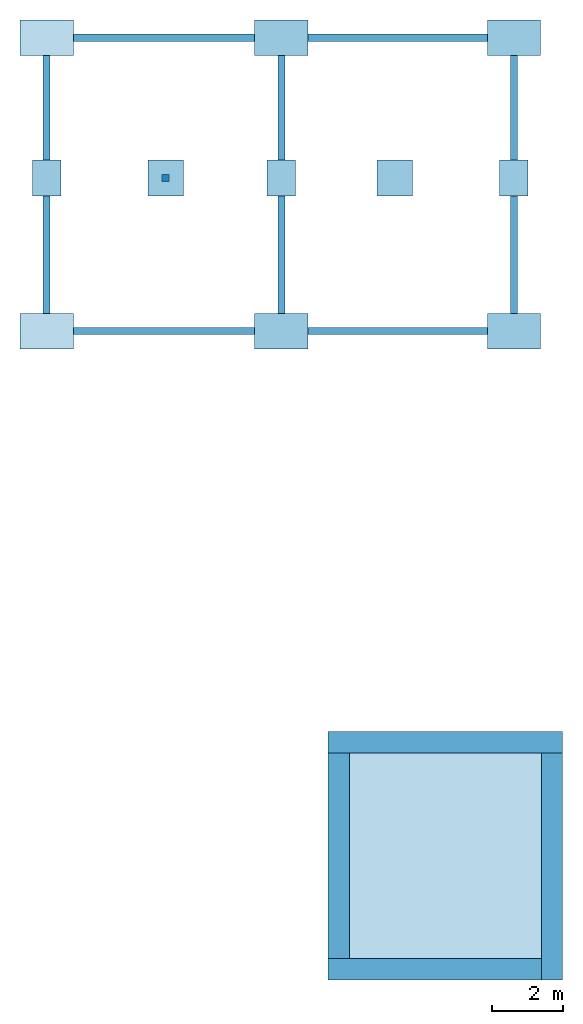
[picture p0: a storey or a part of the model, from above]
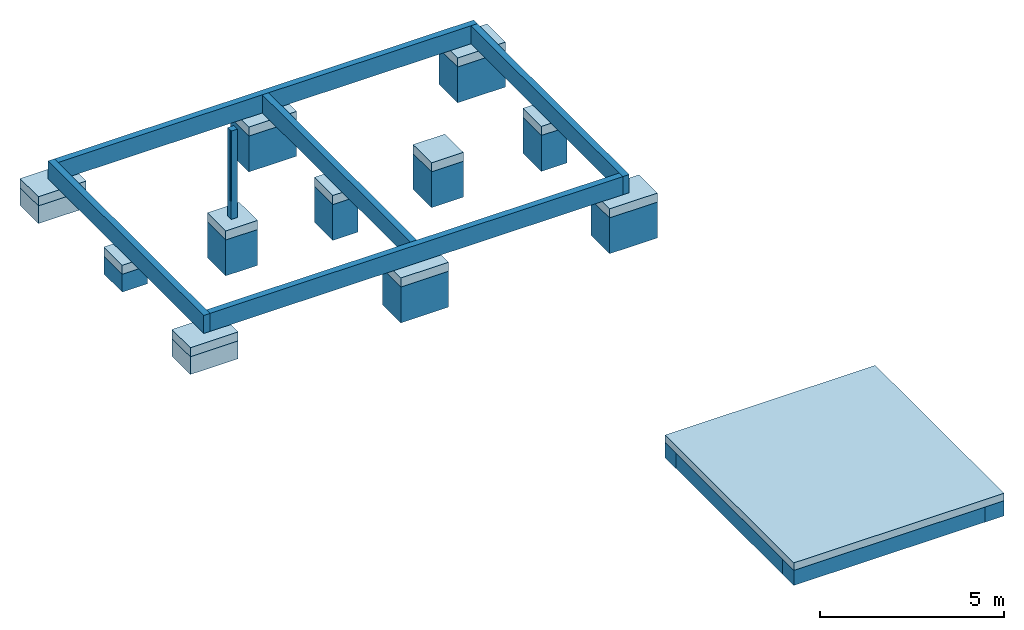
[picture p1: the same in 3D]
Properties of the parts of a building model (IFC2X3)

# File
Description: ViewDefinition [CoordinationView, QuantityTakeOffAddOnView, FMHandOverView]
Time: 2016-03-23T11:02:19
Written by: The EXPRESS Data Manager Version 5.02.0100.07 : 28 Aug 2013
Made in: 20150714_1515(x64) - Exporter 16.3.0.0 - Interface alternative d'export 16.3.0.0
Comment: STEP Physical File produced by: The EXPRESS Data Manager Version 5.02.0100.07 : 28 Aug 2013 * Module: EDMstepFileFactory/EDMstandAlone * Creation date: Wed Mar 23 11:02:19 2016 * Host: St�phaneBertran * Database: C:\Users\STPHAN~1\AppData\Local\Temp\{4BC35CA4-EAC2-46B8-98C0-8E4794780E52}\ifc * Database version: 5507 * Database creation date: Wed Mar 23 11:02:09 2016 * Schema: IFC2X3 * Model: DataRepository.ifc * Model creation date: Wed Mar 23 11:02:10 2016 * Header model: DataRepository.ifc_HeaderModel * Header model creation date: Wed Mar 23 11:02:10 2016 * EDMuser: sdai-user * EDMgroup: sdai-group * License ID and type: 5605 : Permanent license. Expiry date: * EDMstepFileFactory options: 020000

# IfcProject
LongName: E:\02 Année scolaire 2015 2016\01 Seconde TEBEE\07 Projet Damparis\Travail demandé\Nouveau dossier\pavillon et garage.ifc

# IfcSite, Surface:187648
RefLatitude: 48, 51, 23, 999632; RefLongitude: 2, 21, 3, 553904; RefElevation: 0 m

# IfcBuilding
Pset_BuildingCommon - NumberOfStoreys: 4

# IfcBuildingStorey (4)
Name | LongName | Elevation (m)
soubassement | soubassement | -0.6
Rez de chaussée | Rez de chaussée | 0
Plan étage | Plan étage | 2.74
Plan de couverture | Plan de couverture | 5.3

# IfcSpace (2)
In: Rez de chaussée
InteriorOrExteriorSpace: INTERNAL
BaseQuantities - NetFloorArea: 19.5488 m2; Height: 2.4384 m; GrossPerimeter: 19.08 m; GrossFloorArea: 19.5488 m2
Name | LongName | Reference
1 | Garage 1 | Garage 1 1
2 | Garage 2 | Garage 2 2

# IfcBeam: Poutre rectangulaire - Béton:200 x 400 mm:273551 (2)
In: Rez de chaussée
Material: Maçonnerie - Béton
Pset_BeamCommon - IsExternal: no; LoadBearing: yes; Slope: 0 deg; Reference: 200 x 400 mm; Span: 6.53 m
Name (Poutre rectangulaire - Béton:200 x 400 mm:...) | GrossVolume (m3)
274924 | 0.21164
275096 | 0.211528

# IfcColumn: 200 x 200 mm (2)
Type - ElementType: 200 x 200 mm; PredefinedType: COLUMN; Material: Maçonnerie - Béton
Pset_ColumnCommon - LoadBearing: no; IsExternal: no; Reference: 200 x 200 mm
Name (Poteau rectangulaire:200 x 200 mm:...) | In | GrossVolume (m3)
187471 | soubassement | 0.115845
187492 | Rez de chaussée | 0.1176 | BaseQuantities - Length: 2.94 m; CrossSectionArea: 0.04 m2; OuterSurfaceArea: 2.432 m2; Pset_ColumnCommon - Slope: 0 deg

# IfcCovering: Plafond composé:Plafond avec isolation, Plafond composé:Plafond avec isolation:277230
In: Plan étage
PredefinedType: CEILING; Material: Maçonnerie - Isolant 0.25 m, Faux-plafond - Trame 600 x 600 0.01 m
Pset_CoveringCommon - Reference: Plafond avec isolation; TotalThickness: 0.26 m
BaseQuantities - GrossCeilingArea: 104.458 m2

# IfcDoor: 93 x 210 - (90), FR_PVC Panneau Plein:93 x 210 - (90):286378
In: Rez de chaussée
Type - OperationType: SINGLE_SWING_LEFT; ParameterTakesPrecedence: no; Sizeable: no; Material: Poignée PVC, PVC Blanc
Type - FR_PVC Panneau Plein:93 x 210 - (90):286378 - PanelOperation: SWINGING
OverallHeight: 2.15 m; OverallWidth: 1.03 m
Pset_DoorCommon - IsExternal: no; Reference: 93 x 210 - (90)
BaseQuantities - Height: 2.1 m; Width: 0.93 m; Area: 1.953 m2

# IfcDoor: 93 x 210 - (90), FR_PVC Panneau Plein:93 x 210 - (90):286377
In: Rez de chaussée
Type - OperationType: SINGLE_SWING_RIGHT; ParameterTakesPrecedence: no; Sizeable: no; Material: Poignée PVC, PVC Blanc
Type - FR_PVC Panneau Plein:93 x 210 - (90):286377 - PanelOperation: SWINGING
OverallHeight: 2.15 m; OverallWidth: 1.03 m
Pset_DoorCommon - IsExternal: no; Reference: 93 x 210 - (90)
BaseQuantities - Height: 2.1 m; Width: 0.93 m; Area: 1.953 m2

# IfcDoor: 96" x 78" (2)
In: Rez de chaussée
Type - ParameterTakesPrecedence: no; Sizeable: no; Classification: B2030410 Overhead Doors (Uniformat); Material: Rubber - Black
OverallHeight: 1.9812 m; OverallWidth: 2.4384 m
Pset_DoorCommon - IsExternal: no; Reference: 96" x 78"
BaseQuantities - Height: 1.9812 m; Width: 2.4384 m; Area: 4.83096 m2
Name (Overhead-Sectional-Flush:96" x 78":...)
286375
286376

# IfcDoor: PF 1.30 x 2.15 (3)
In: Rez de chaussée
Type - OperationType: DOUBLE_DOOR_SINGLE_SWING; ParameterTakesPrecedence: no; Sizeable: no; Classification: C1020 Interior Doors (Uniformat); Material: Glass, PVC - Blanc
Type - Double-Glass 1_no trim:PF 1.30 x 2.15:205899 - PanelOperation: SWINGING
OverallHeight: 2.15 m; OverallWidth: 1.3 m
Pset_DoorCommon - IsExternal: no; Reference: PF 1.30 x 2.15
BaseQuantities - Height: 2.15 m; Width: 1.3 m; Area: 2.795 m2
Name (Double-Glass 1_no trim:PF 1.30 x 2.15:...)
205899
205926
205958

# IfcDoor: PF 1.30 x 2.15, Double-Glass 1_no trim:PF 1.30 x 2.15:206001
In: Rez de chaussée
Type - OperationType: DOUBLE_DOOR_SINGLE_SWING; ParameterTakesPrecedence: no; Sizeable: no; Classification: C1020 Interior Doors (Uniformat); Material: Glass, PVC - Blanc
Type - Double-Glass 1_no trim:PF 1.30 x 2.15:206001 - PanelOperation: SWINGING
OverallHeight: 2.15 m; OverallWidth: 1.3 m
Pset_DoorCommon - IsExternal: no; Reference: PF 1.30 x 2.15
BaseQuantities - Height: 2.15 m; Width: 1.3 m; Area: 2.795 m2

# IfcDoor: PF 1.60 x 2.15 (2)
In: Rez de chaussée
Type - OperationType: DOUBLE_DOOR_SINGLE_SWING; ParameterTakesPrecedence: no; Sizeable: no; Classification: C1020 Interior Doors (Uniformat); Material: Glass, PVC - Blanc
Type - Double-Glass 1_no trim:PF 1.60 x 2.15:205161 - PanelOperation: SWINGING
OverallHeight: 2.15 m; OverallWidth: 1.6 m
Pset_DoorCommon - IsExternal: no; Reference: PF 1.60 x 2.15
BaseQuantities - Height: 2.15 m; Width: 1.6 m; Area: 3.44 m2
Name (Double-Glass 1_no trim:PF 1.60 x 2.15:...)
205161
205435

# IfcDoor: PP (0.83m x 2.04m) (5)
Type - OperationType: SINGLE_SWING_LEFT; ParameterTakesPrecedence: no; Sizeable: no; Material: Finition Peinture - Blanc satiné, Bois - Panneau de porte, Bois - Cadre de porte
Type - Int. Simple:PP (0.83m x 2.04m):187630 - PanelOperation: SWINGING
OverallHeight: 2.075 m; OverallWidth: 0.9 m
Pset_DoorCommon - IsExternal: no; Reference: PP (0.83m x 2.04m)
BaseQuantities - Height: 2.04 m; Width: 0.83 m; Area: 1.6932 m2
Name (Int. Simple:PP (0.83m x 2.04m):...) | In
187630 | Plan étage
187632 | Plan étage
187636 | Plan étage
187641 | Plan étage
206475 | Rez de chaussée

# IfcDoor: PP (0.83m x 2.04m), Int. Simple:PP (0.83m x 2.04m):187644
In: Plan étage
Type - OperationType: SINGLE_SWING_LEFT; ParameterTakesPrecedence: no; Sizeable: no; Material: Finition Peinture - Blanc satiné, Bois - Panneau de porte, Bois - Cadre de porte
Type - Int. Simple:PP (0.83m x 2.04m):187644 - PanelOperation: SWINGING
OverallHeight: 2.075 m; OverallWidth: 0.9 m
Pset_DoorCommon - IsExternal: no; Reference: PP (0.83m x 2.04m)
BaseQuantities - Height: 2.04 m; Width: 0.83 m; Area: 1.6932 m2

# IfcDoor: PP (0.83m x 2.04m), Int. Simple:PP (0.83m x 2.04m):206517
In: Rez de chaussée
Type - OperationType: SINGLE_SWING_LEFT; ParameterTakesPrecedence: no; Sizeable: no; Material: Finition Peinture - Blanc satiné, Bois - Panneau de porte, Bois - Cadre de porte
Type - Int. Simple:PP (0.83m x 2.04m):206517 - PanelOperation: SWINGING
OverallHeight: 2.075 m; OverallWidth: 0.9 m
Pset_DoorCommon - IsExternal: no; Reference: PP (0.83m x 2.04m)
BaseQuantities - Height: 2.04 m; Width: 0.83 m; Area: 1.6932 m2

# IfcDoor: PP (0.83m x 2.04m), Int. Simple:PP (0.83m x 2.04m):206587
In: Rez de chaussée
Type - OperationType: SINGLE_SWING_LEFT; ParameterTakesPrecedence: no; Sizeable: no; Material: Finition Peinture - Blanc satiné, Bois - Panneau de porte, Bois - Cadre de porte
Type - Int. Simple:PP (0.83m x 2.04m):206587 - PanelOperation: SWINGING
OverallHeight: 2.075 m; OverallWidth: 0.9 m
Pset_DoorCommon - IsExternal: no; Reference: PP (0.83m x 2.04m)
BaseQuantities - Height: 2.04 m; Width: 0.83 m; Area: 1.6932 m2

# IfcDoor: PP (0.83m x 2.04m) (6)
Type - OperationType: SINGLE_SWING_RIGHT; ParameterTakesPrecedence: no; Sizeable: no; Material: Finition Peinture - Blanc satiné, Bois - Panneau de porte, Bois - Cadre de porte
Type - Int. Simple:PP (0.83m x 2.04m):187629 - PanelOperation: SWINGING
OverallHeight: 2.075 m; OverallWidth: 0.9 m
Pset_DoorCommon - IsExternal: no; Reference: PP (0.83m x 2.04m)
BaseQuantities - Height: 2.04 m; Width: 0.83 m; Area: 1.6932 m2
Name (Int. Simple:PP (0.83m x 2.04m):...) | In
187629 | Plan étage
187631 | Plan étage
187635 | Plan étage
187647 | Plan étage
206419 | Rez de chaussée
206630 | Rez de chaussée

# IfcDoor: PP (0.83m x 2.04m) (2)
Type - OperationType: SINGLE_SWING_RIGHT; ParameterTakesPrecedence: no; Sizeable: no; Material: Finition Peinture - Blanc satiné, Bois - Panneau de porte, Bois - Cadre de porte
Type - Int. Simple:PP (0.83m x 2.04m):187633 - PanelOperation: SWINGING
OverallHeight: 2.075 m; OverallWidth: 0.9 m
Pset_DoorCommon - IsExternal: no; Reference: PP (0.83m x 2.04m)
BaseQuantities - Height: 2.04 m; Width: 0.83 m; Area: 1.6932 m2
Name (Int. Simple:PP (0.83m x 2.04m):...) | In
187633 | Plan étage
206556 | Rez de chaussée

# IfcDoor: PP Lisse (0.90m x 2.15m), Porte d'entrée:PP Lisse (0.90m x 2.15m):187528
In: Rez de chaussée
Type - OperationType: SINGLE_SWING_LEFT; ParameterTakesPrecedence: no; Sizeable: no; Material: Porte d'entrée - Poignée, Porte d'entrée - Panneau, Porte d'entrée - Cadre
Type - Porte d'entrée:PP Lisse (0.90m x 2.15m):187528 - PanelOperation: SWINGING
OverallHeight: 2.19 m; OverallWidth: 0.98 m
Pset_DoorCommon - IsExternal: no; Reference: PP Lisse (0.90m x 2.15m)
BaseQuantities - Height: 2.15 m; Width: 0.9 m; Area: 1.935 m2

# IfcDoor: PP Lisse (0.90m x 2.15m), Porte d'entrée:PP Lisse (0.90m x 2.15m):205515
In: Rez de chaussée
Type - OperationType: SINGLE_SWING_RIGHT; ParameterTakesPrecedence: no; Sizeable: no; Material: Porte d'entrée - Poignée, Porte d'entrée - Panneau, Porte d'entrée - Cadre
Type - Porte d'entrée:PP Lisse (0.90m x 2.15m):205515 - PanelOperation: SWINGING
OverallHeight: 2.19 m; OverallWidth: 0.98 m
Pset_DoorCommon - IsExternal: no; Reference: PP Lisse (0.90m x 2.15m)
BaseQuantities - Height: 2.15 m; Width: 0.9 m; Area: 1.935 m2

# IfcDoor: Placard coulissante - 3 panneaux (2)
In: Rez de chaussée
Type - OperationType: SLIDING_TO_RIGHT; ParameterTakesPrecedence: no; Sizeable: no; Material: Placard - Profil, Placard - Encadrement, Placard - Porte
Type - Placard coulissante - 3 panneaux:Placard coulissante - 3 panneaux:187537 - PanelOperation: SLIDING
OverallHeight: 2.1 m; OverallWidth: 1.7 m
Pset_DoorCommon - IsExternal: no; Reference: Placard coulissante - 3 panneaux
BaseQuantities - Height: 2.1 m; Width: 1.7 m; Area: 3.57 m2
Name (Placard coulissante - 3 panneaux:Placard coulissante - 3 panneaux:...)
187537
204080

# IfcOpeningElement: Opening (46)
Name | In | Depth (m) | Height (m) | Width (m)
Mur de base:Int. plâtre 50 mm:187323 | Rez de chaussée | 6.2591 | 6.2591 | 3.12955
Mur de base:Int. plâtre 50 mm:187323 | Rez de chaussée | 0.05 | BaseQuantities - Area: 0.465543 m2
Mur de base:Int. plâtre 50 mm:187338 | Rez de chaussée | 6.2591 | 6.2591 | 3.12955
Overhead-Sectional-Flush:96" x 78":286376:1 | Rez de chaussée | 0.22 | 2.4384 | 1.9812
Mur de base:Int. plâtre 50 mm:187338 | Rez de chaussée | 0.05 | BaseQuantities - Area: 0.465543 m2
Mur de base:Int. plâtre 50 mm:187425 | Rez de chaussée | 0.05 | 0.025 | 2.1
Mur de base:Int. plâtre 50 mm:187440 | Rez de chaussée | 0.05 | 0.025 | 2.1
Mur de base:Int. plâtre 50 mm:187620 | Plan étage | 0.9 | 2.075 | 0.05
Mur de base:Int. plâtre 50 mm:187634 | Plan étage | 0.9 | 2.075 | 0.05
Overhead-Sectional-Flush:96" x 78":286375:1 | Rez de chaussée | 0.22 | 2.4384 | 1.9812
Double-Glass 1_no trim:PF 1.30 x 2.15:205899:1 | Rez de chaussée | 0.34 | 1.3 | 2.15
Double-Glass 1_no trim:PF 1.30 x 2.15:205926:1 | Rez de chaussée | 0.34 | 1.3 | 2.15
Double-Glass 1_no trim:PF 1.30 x 2.15:205958:1 | Rez de chaussée | 0.34 | 1.3 | 2.15
Double-Glass 1_no trim:PF 1.30 x 2.15:206001:1 | Rez de chaussée | 0.34 | 1.3 | 2.15
2 x Mur de base:Mur de base Ext. Parpaing 20 + Isolant 12:187495 | Rez de chaussée
Double-Glass 1_no trim:PF 1.60 x 2.15:205161:1 | Rez de chaussée | 0.34 | 1.6 | 2.15
Double-Glass 1_no trim:PF 1.60 x 2.15:205435:1 | Rez de chaussée | 0.34 | 1.6 | 2.15
Int. Simple:PP (0.83m x 2.04m):206419:1 | Rez de chaussée | 0.05 | 0.9 | 2.075
Int. Simple:PP (0.83m x 2.04m):206517:1 | Rez de chaussée | 0.05 | 0.9 | 2.075
Int. Simple:PP (0.83m x 2.04m):206587:1 | Rez de chaussée | 0.05 | 0.9 | 2.075
Placard coulissante - 3 panneaux:Placard coulissante - 3 panneaux:204080:1 | Rez de chaussée | 0.05 | 1.7 | 2.1
Int. Simple:PP (0.83m x 2.04m):206475:1 | Rez de chaussée | 0.05 | 0.9 | 2.075
Int. Simple:PP (0.83m x 2.04m):206556:1 | Rez de chaussée | 0.05 | 0.9 | 2.075
Int. Simple:PP (0.83m x 2.04m):206630:1 | Rez de chaussée | 0.05 | 0.9 | 2.075
Placard coulissante - 3 panneaux:Placard coulissante - 3 panneaux:187537:1 | Rez de chaussée | 0.05 | 1.7 | 2.1
Int. Simple:PP (0.83m x 2.04m):187630:1 | Plan étage | 0.05 | 0.9 | 2.075
Int. Simple:PP (0.83m x 2.04m):187631:1 | Plan étage | 0.05 | 0.9 | 2.075
Int. Simple:PP (0.83m x 2.04m):187629:1 | Plan étage | 0.05 | 0.9 | 2.075
Int. Simple:PP (0.83m x 2.04m):187633:1 | Plan étage | 0.05 | 0.9 | 2.075
Int. Simple:PP (0.83m x 2.04m):187632:1 | Plan étage | 0.05 | 0.9 | 2.075
Int. Simple:PP (0.83m x 2.04m):187635:1 | Plan étage | 0.05 | 0.9 | 2.075
Int. Simple:PP (0.83m x 2.04m):187636:1 | Plan étage | 0.05 | 0.9 | 2.075
Int. Simple:PP (0.83m x 2.04m):187641:1 | Plan étage | 0.05 | 0.9 | 2.075
Int. Simple:PP (0.83m x 2.04m):187644:1 | Plan étage | 0.05 | 0.9 | 2.075
Int. Simple:PP (0.83m x 2.04m):187647:1 | Plan étage | 0.05 | 0.9 | 2.075
4 x Mur de base:Mur de base Ext. Parpaing 20 + Isolant 12:188922 | Plan étage
4 x Mur de base:Mur de base Ext. Parpaing 20 + Isolant 12:188923 | Plan étage
2 x Mur de base:Ext.BBM + enduit 22:286370 | Rez de chaussée

# IfcRailing: Garde-corps:Type Bateau (3)
In: Rez de chaussée
Material: Peinture - grise, Bois - Pin
Pset_RailingCommon - IsExternal: no; Reference: Type Bateau; Height: 1.2192 m
Name (Garde-corps:Type Bateau:...) | Length (m)
223490 | 4.90433
227138 | 4.38474
271948 | 4.38474

# IfcRoof: Toit de base:Toit - 100 mm 2, Toit de base:Toit - 100 mm 2:286381
In: Plan étage
Pset_RoofCommon - IsExternal: yes; Reference: Toit - 100 mm 2; TotalArea: 61.8782 m2; ProjectedArea: 53.04 m2

# IfcRoof: Toit de base:Toit - 200 mm, Toit de base:Toit - 200 mm:277896
In: Plan de couverture
Pset_RoofCommon - IsExternal: yes; Reference: Toit - 200 mm; TotalArea: 143.325 m2; ProjectedArea: 122.854 m2

# IfcSlab: Base rectangulaire:1000mm x 1000mm x 300mm (2)
In: soubassement
PredefinedType: FLOOR; Material: Béton - Béton coulé sur place
Pset_SlabCommon - IsExternal: no; LoadBearing: yes; PitchAngle: 0 deg; Reference: 1000mm x 1000mm x 300mm
BaseQuantities - GrossArea: 1 m2; GrossVolume: 0.3 m3; Perimeter: 4 m; Width: 0.3 m
Name (Base rectangulaire:1000mm x 1000mm x 300mm:...)
215258
215662

# IfcSlab: Base rectangulaire:1500mm x 1000mm x 300mm (6)
In: soubassement
PredefinedType: FLOOR; Material: Béton - Béton coulé sur place
Pset_SlabCommon - IsExternal: no; LoadBearing: yes; Reference: 1500mm x 1000mm x 300mm; PitchAngle: 0 deg
BaseQuantities - GrossArea: 1.5 m2; GrossVolume: 0.45 m3; Perimeter: 5 m; Width: 0.3 m
Name (Base rectangulaire:1500mm x 1000mm x 300mm:...)
213384
213606
213688
213876
214012
214106

# IfcSlab: Base rectangulaire:800mm x 1000mm x 300mm (3)
In: soubassement
PredefinedType: FLOOR; Material: Béton - Béton coulé sur place
Pset_SlabCommon - IsExternal: no; LoadBearing: yes; PitchAngle: 0 deg; Reference: 800mm x 1000mm x 300mm
BaseQuantities - GrossArea: 0.8 m2; GrossVolume: 0.24 m3; Perimeter: 3.6 m; Width: 0.3 m
Name (Base rectangulaire:800mm x 1000mm x 300mm:...)
214496
214606
214724

# IfcSlab: Base rectangulaire:gros beton 1000mm x 1000mm x 1190mm (2)
In: soubassement
PredefinedType: FLOOR; Material: Béton - Béton coulé sur place
Pset_SlabCommon - IsExternal: no; LoadBearing: yes; PitchAngle: 0 deg; Reference: gros beton 1000mm x 1000mm x 1190mm
BaseQuantities - GrossArea: 1 m2; GrossVolume: 1.19 m3; Perimeter: 4 m; Width: 1.19 m
Name (Base rectangulaire:gros beton 1000mm x 1000mm x 1190mm:...)
216552
216665

# IfcSlab: Base rectangulaire:gros beton 1000mm x 800mm x 1190mm (2)
In: soubassement
PredefinedType: FLOOR; Material: Béton - Béton coulé sur place
Pset_SlabCommon - IsExternal: no; LoadBearing: yes; PitchAngle: 0 deg; Reference: gros beton 1000mm x 800mm x 1190mm
BaseQuantities - GrossArea: 0.8 m2; GrossVolume: 0.952 m3; Perimeter: 3.6 m; Width: 1.19 m
Name (Base rectangulaire:gros beton 1000mm x 800mm x 1190mm:...)
218791
218905

# IfcSlab: Base rectangulaire:gros beton 1000mm x 800mm x 590mm, Base rectangulaire:gros beton 1000mm x 800mm x 590mm:218621
In: soubassement
PredefinedType: FLOOR; Material: Béton - Béton coulé sur place
Pset_SlabCommon - IsExternal: no; LoadBearing: yes; PitchAngle: 0 deg; Reference: gros beton 1000mm x 800mm x 590mm
BaseQuantities - GrossArea: 0.8 m2; GrossVolume: 0.472 m3; Perimeter: 3.6 m; Width: 0.59 m

# IfcSlab: Base rectangulaire:gros beton 1500mm x 1000mm x 1190mm (4)
In: soubassement
PredefinedType: FLOOR; Material: Béton - Béton coulé sur place
Pset_SlabCommon - IsExternal: no; LoadBearing: yes; PitchAngle: 0 deg; Reference: gros beton 1500mm x 1000mm x 1190mm
BaseQuantities - GrossArea: 1.5 m2; GrossVolume: 1.785 m3; Perimeter: 5 m; Width: 1.19 m
Name (Base rectangulaire:gros beton 1500mm x 1000mm x 1190mm:...)
217089
217251
217483
218347

# IfcSlab: Base rectangulaire:gros beton 1500mm x 1000mm x 590mm (2)
In: soubassement
PredefinedType: FLOOR; Material: Béton - Béton coulé sur place
Pset_SlabCommon - IsExternal: no; LoadBearing: yes; PitchAngle: 0 deg; Reference: gros beton 1500mm x 1000mm x 590mm
BaseQuantities - GrossArea: 1.5 m2; GrossVolume: 0.885 m3; Perimeter: 5 m; Width: 0.59 m
Name (Base rectangulaire:gros beton 1500mm x 1000mm x 590mm:...)
216937
217617

# IfcSlab: Sol:Dalle Béton -160 + 60 mm, Sol:Dalle Béton -160 + 60 mm:276078
In: Plan étage
PredefinedType: FLOOR; Material: <Unnamed> 0.01 m, Maçonnerie - Béton 0.22 m, <Unnamed> 0.01 m
Pset_SlabCommon - IsExternal: no; LoadBearing: yes; PitchAngle: 0 deg; Reference: Dalle Béton -160 + 60 mm
BaseQuantities - GrossArea: 96.1667 m2; GrossVolume: 23.08 m3; Perimeter: 42.04 m; Width: 0.24 m

# IfcSlab: Sol:Dalle en béton - 13 (2)
In: Rez de chaussée
PredefinedType: FLOOR; Material: Maçonnerie - Béton 0.13 m, Maçonnerie - Isolant 1 0.08 m
Pset_SlabCommon - IsExternal: no; LoadBearing: yes; PitchAngle: 0 deg; Reference: Dalle en béton - 13
BaseQuantities - Width: 0.21 m
Name (Sol:Dalle en béton - 13:...) | GrossArea (m2) | GrossVolume (m3) | Perimeter (m)
219665 | 51.181 | 10.748 | 28.82
220152 | 51.6646 | 10.8496 | 28.94

# IfcSlab: Sol:Dalle en béton - 250 mm, Sol:Dalle en béton - 250 mm:286388
In: soubassement
PredefinedType: FLOOR; Material: Maçonnerie - Béton 0.25 m
Pset_SlabCommon - IsExternal: no; LoadBearing: yes; PitchAngle: 0 deg; Reference: Dalle en béton - 250 mm
BaseQuantities - GrossArea: 46.2 m2; GrossVolume: 11.55 m3; Perimeter: 27.2 m; Width: 0.25 m

# IfcSlab: Toit de base:Toit - 100 mm 2 (2)
In: Plan étage
PredefinedType: ROOF; Material: Toit par défaut 0.1 m
Pset_SlabCommon - LoadBearing: yes; IsExternal: yes; Reference: Toit - 100 mm 2; PitchAngle: 31 deg
BaseQuantities - GrossArea: 2.87434 m2; GrossVolume: 0.287434 m3; Perimeter: 22.6997 m; Width: 0.1 m

# IfcSlab: Toit de base:Toit - 200 mm (2)
In: Plan de couverture
PredefinedType: ROOF; Material: Toit par défaut 0.2 m
Pset_SlabCommon - LoadBearing: yes; IsExternal: yes; Reference: Toit - 200 mm; PitchAngle: 31 deg
BaseQuantities - GrossArea: 6.65767 m2; GrossVolume: 1.33153 m3; Perimeter: 37.6897 m; Width: 0.2 m

# IfcStair: Escalier:Monobloc:28673 (5)
In: Rez de chaussée
Name (Escalier:Monobloc:...) | IsExternal | Reference | NumberOfRiser = NumberOfTreads | RiserHeight (m) | TreadLength (m)
223436 | no | Monobloc | 12 | 0.182667 | 0.264667
225808 | Material: Maçonnerie - Béton
225808 | no | Monobloc | 15 | 0.182667 | 0.264667
271926 | Material: Maçonnerie - Béton
271926 | no | Monobloc | 15 | 0.182667 | 0.264667

# IfcWallStandardCase: Mur de base:Ext. longrine 20 x 60 (5)
In: soubassement
Type - PredefinedType: STANDARD; Material: Maçonnerie - Voile BA 0.2 m
BaseQuantities - Height: 0.6 m; Width: 0.2 m
Pset_WallCommon - ExtendToStructure: no; LoadBearing: yes; IsExternal: yes; Reference: Ext. longrine 20 x 60
Name (Mur de base:Ext. longrine 20 x 60:...) | Length (m) | GrossFootprintArea (m2) | GrossSideArea (m2) | GrossVolume (m3)
212326 | 8.46 | 1.692 | 13.776 | 1.0152
212358 | 13.16 | 2.632 | 21.296 | 1.5792
212399 | 8.26 | 1.652 | 13.456 | 0.9912
212434 | 12.96 | 2.592 | 20.976 | 1.5552
212556 | 8.06 | 1.612 | 13.136 | 0.9672

# IfcWallStandardCase: Mur de base:Ext.BBM + enduit 22 (6)
Type - PredefinedType: STANDARD; Material: Maçonnerie - Enduit 0.02 m, Maçonnerie - Béton 0.2 m
BaseQuantities - Width: 0.22 m
Pset_WallCommon - LoadBearing: no; IsExternal: yes; ExtendToStructure: yes; Reference: Ext.BBM + enduit 22
Name (Mur de base:Ext.BBM + enduit 22:...) | In | Height (m) | Length (m) | GrossFootprintArea (m2) | GrossSideArea (m2) | GrossVolume (m3)
286370 | Rez de chaussée | 2.58219 | 6.6 | 1.452 | 31.3123 | 2.75039
286371 | Rez de chaussée | 2.74 | 6.78 | 1.4916 | 41.0906 | 4.06703
286371 | Plan étage | 1.81301 | 6.78 | 1.4916 | 13.8175 | 1.20351
286372 | Rez de chaussée | 2.58219 | 6.38 | 1.4036 | 18.6732 | 1.40597
286373 | Rez de chaussée | 2.74 | 6.56 | 1.4432 | 39.9077 | 3.94525
286373 | Plan étage | 1.81301 | 6.56 | 1.4432 | 13.8175 | 1.20351

# IfcWallStandardCase: Mur de base:Ext.BBM 20 cm (2)
Type - PredefinedType: STANDARD; Material: Mur par défaut 0.2 m
BaseQuantities - Length: 6.56 m; Width: 0.2 m; GrossFootprintArea: 1.312 m2
Pset_WallCommon - LoadBearing: no; IsExternal: yes; ExtendToStructure: yes; Reference: Ext.BBM 20 cm
Name (Mur de base:Ext.BBM 20 cm:...) | In | Height (m) | GrossSideArea (m2) | GrossVolume (m3)
286374 | Rez de chaussée | 2.74 | 39.5403 | 3.58659
286374 | Plan étage | 1.81301 | 13.556 | 1.0941

# IfcWallStandardCase: Mur de base:Int. plâtre 50 mm (34)
Type - PredefinedType: STANDARD; Material: Maçonnerie - Isolant(1) 0.05 m
BaseQuantities - Width: 0.05 m
Pset_WallCommon - Reference: Int. plâtre 50 mm; LoadBearing: no; ExtendToStructure: no; IsExternal: no
Name (Mur de base:Int. plâtre 50 mm:...) | In | Height (m) | Length (m) | GrossFootprintArea (m2) | GrossSideArea (m2) | GrossVolume (m3)
187323 | Rez de chaussée | 2.52 | 1.36 | 0.068 | 5.62202 | 0.130853
187338 | Rez de chaussée | 2.52 | 1.365 | 0.06825 | 5.63996 | 0.131289
187425 | Rez de chaussée | 2.52 | 0.61 | 0.0305 | 3.3874 | 0.07686
187440 | Rez de chaussée | 2.52 | 0.61 | 0.0305 | 3.3874 | 0.07686
187517 | Rez de chaussée | 2.52 | 3.64 | 0.182 | 18.9616 | 0.45864
187518 | Rez de chaussée | 2.52 | 3.045 | 0.15225 | 12.4658 | 0.290295
187519 | Rez de chaussée | 2.52 | 1.55 | 0.0775 | 4.7815 | 0.101925
187520 | Rez de chaussée | 2.52 | 3.39 | 0.1695 | 14.2391 | 0.333765
187521 | Rez de chaussée | 2.52 | 0.56 | 0.028 | 3.1304 | 0.07056
187522 | Rez de chaussée | 2.52 | 2.56 | 0.128 | 6.6504 | 0.14406
187531 | Rez de chaussée | 2.52 | 3.63 | 0.1815 | 18.9102 | 0.45738
187532 | Rez de chaussée | 2.52 | 3.04 | 0.152 | 12.4401 | 0.289665
187533 | Rez de chaussée | 2.52 | 1.55 | 0.0775 | 4.7815 | 0.101925
187534 | Rez de chaussée | 2.52 | 3.39 | 0.1695 | 14.2391 | 0.333765
187535 | Rez de chaussée | 2.52 | 0.56 | 0.028 | 3.1304 | 0.07056
187536 | Rez de chaussée | 2.52 | 2.39 | 0.1195 | 5.7766 | 0.12264
187620 | Plan étage | 2.51 | 7.84 | 0.392 | 33.5168 | 0.79717
187621 | Plan étage | 2.51 | 3.1 | 0.155 | 12.6855 | 0.295675
187622 | Plan étage | 2.51 | 1.085 | 0.05425 | 5.8062 | 0.136167
187623 | Plan étage | 2.51 | 1.31 | 0.0655 | 3.5207 | 0.07103
187624 | Plan étage | 2.51 | 1.175 | 0.05875 | 6.267 | 0.147462
187625 | Plan étage | 2.51 | 3.87 | 0.1935 | 20.0654 | 0.485685
187626 | Plan étage | 2.51 | 3.07 | 0.1535 | 15.9694 | 0.385285
187627 | Plan étage | 2.51 | 1.045 | 0.05225 | 2.1639 | 0.0377725
187628 | Plan étage | 2.51 | 0.34 | 0.017 | 1.9918 | 0.04267
187634 | Plan étage | 2.51 | 7.84 | 0.392 | 33.5168 | 0.79717
187637 | Plan étage | 2.51 | 3.08 | 0.154 | 12.5831 | 0.293165
187638 | Plan étage | 2.51 | 1.035 | 0.05175 | 5.5502 | 0.129892
187639 | Plan étage | 2.51 | 1.145 | 0.05725 | 6.1134 | 0.143697
187640 | Plan étage | 2.5 | 3.09 | 0.1545 | 16.009 | 0.38625
187642 | Plan étage | 2.51 | 3.855 | 0.19275 | 19.9886 | 0.483803
187643 | Plan étage | 2.51 | 1.31 | 0.0655 | 3.5207 | 0.07103
187645 | Plan étage | 2.51 | 1.075 | 0.05375 | 2.3175 | 0.0415375
187646 | Plan étage | 2.51 | 0.34 | 0.017 | 1.9918 | 0.04267

# IfcWallStandardCase: Mur de base:Mur de base Ext. Parpaing 20 (2)
In: Plan de couverture
Type - PredefinedType: STANDARD; Material: Maçonnerie - Enduit 0.02 m, Maçonnerie - Parpaing 0.2 m
BaseQuantities - Height: 2.62164 m; Length: 8.5 m; Width: 0.22 m; GrossFootprintArea: 1.87 m2; GrossSideArea: 26.9433 m2; GrossVolume: 2.5148 m3
Pset_WallCommon - LoadBearing: yes; IsExternal: yes; Reference: Mur de base Ext. Parpaing 20; ExtendToStructure: yes
Name (Mur de base:Mur de base Ext. Parpaing 20:...)
278254
278265

# IfcWallStandardCase: Mur de base:Mur de base Ext. Parpaing 20 + Isolant 12 (10)
Type - PredefinedType: STANDARD; Material: Maçonnerie - Enduit 0.02 m, Maçonnerie - Parpaing 0.2 m, Maçonnerie - Isolant 0.11 m, Maçonnerie - Isolant 1 0.01 m
BaseQuantities - Width: 0.34 m
Pset_WallCommon - ExtendToStructure: no; Reference: Mur de base Ext. Parpaing 20 + Isolant 12; LoadBearing: yes; IsExternal: yes
Name (Mur de base:Mur de base Ext. Parpaing 20 + Isolant 12:...) | In | Height (m) | Length (m) | GrossFootprintArea (m2) | GrossSideArea (m2) | GrossVolume (m3)
187353 | Rez de chaussée | 2.74 | 8.5 | 2.89 | 54.2813 | 7.79959
187389 | Rez de chaussée | 2.74 | 8.5 | 2.89 | 54.2813 | 7.79871
187494 | Rez de chaussée | 2.74 | 12.72 | 4.3248 | 63.7064 | 8.04875
187495 | Rez de chaussée | 2.74 | 12.72 | 4.3248 | 64.3806 | 8.13453
187561 | Plan étage | 2.56 | 8.5 | 2.89 | 51.0288 | 7.3474
187583 | Plan étage | 2.56 | 8.5 | 2.89 | 51.0288 | 7.3474
188922 | Plan étage | 2.56 | 12.72 | 4.3248 | 72.1332 | 9.17266
188922 | Plan de couverture | 0.1 | 12.72 | 4.3248 | 8.1848 | 0.27984
188923 | Plan étage | 2.56 | 12.72 | 4.3248 | 74.0891 | 9.76134
188923 | Plan de couverture | 0.1 | 12.72 | 4.3248 | 8.1848 | 0.27984

# IfcWallStandardCase: Mur de base:Mur de base Refend Ext. Parpaing 20 + Isolant 7 (2)
Type - PredefinedType: STANDARD; Material: Maçonnerie - Isolant 1 0.01 m, Maçonnerie - Bloc de béton (2) 0.2 m, Maçonnerie - Isolant 0.06 m, Maçonnerie - Isolant 1 0.01 m
BaseQuantities - Length: 7.82 m; Width: 0.28 m; GrossFootprintArea: 2.1896 m2
Pset_WallCommon - ExtendToStructure: no; LoadBearing: yes; IsExternal: yes; Reference: Mur de base Refend Ext. Parpaing 20 + Isolant 7
Name (Mur de base:Mur de base Refend Ext. Parpaing 20 + Isolant 7:...) | In | Height (m) | GrossSideArea (m2) | GrossVolume (m3)
187506 | Rez de chaussée | 2.498 | 44.8468 | 5.46962
187610 | Plan étage | 2.5 | 44.8792 | 5.474

# IfcWallStandardCase: Mur de base:fond 60 cm (4)
In: soubassement
Type - PredefinedType: STANDARD; Material: FONDATIONS 0.6 m
BaseQuantities - Height: 0.5 m; Width: 0.6 m
Pset_WallCommon - ExtendToStructure: no; LoadBearing: yes; IsExternal: yes; Reference: fond 60 cm
Name (Mur de base:fond 60 cm:...) | Length (m) | GrossFootprintArea (m2) | GrossSideArea (m2) | GrossVolume (m3)
286395 | 6.6 | 3.96 | 15.12 | 1.98
286397 | 6.4 | 3.84 | 14.68 | 1.92
286399 | 6 | 3.6 | 13.8 | 1.8
286401 | 5.8 | 3.48 | 13.36 | 1.74

# IfcWindow: 60x65 (2)
In: Plan étage
Type - ParameterTakesPrecedence: no; Sizeable: no; Material: Appui, Huisserie, Verre
OverallHeight: 0.959972 m; OverallWidth: 0.7 m
Pset_WindowCommon - IsExternal: yes; Reference: 60x65
BaseQuantities - Height: 0.65 m; Width: 0.6 m; Area: 0.39 m2
Name (FR_1 Vantail Appui Béton:60x65:...)
190471
220469

# IfcWindow: 90x135 (6)
In: Plan étage
Type - ParameterTakesPrecedence: no; Sizeable: no; Material: Appui, Huisserie, Verre
OverallHeight: 1.65997 m; OverallWidth: 1 m
Pset_WindowCommon - IsExternal: yes; Reference: 90x135
BaseQuantities - Height: 1.35 m; Width: 0.9 m; Area: 1.215 m2
Name (FR_1 Vantail Appui Béton:90x135:...)
190443
220285
220312
220338
220372
220425
